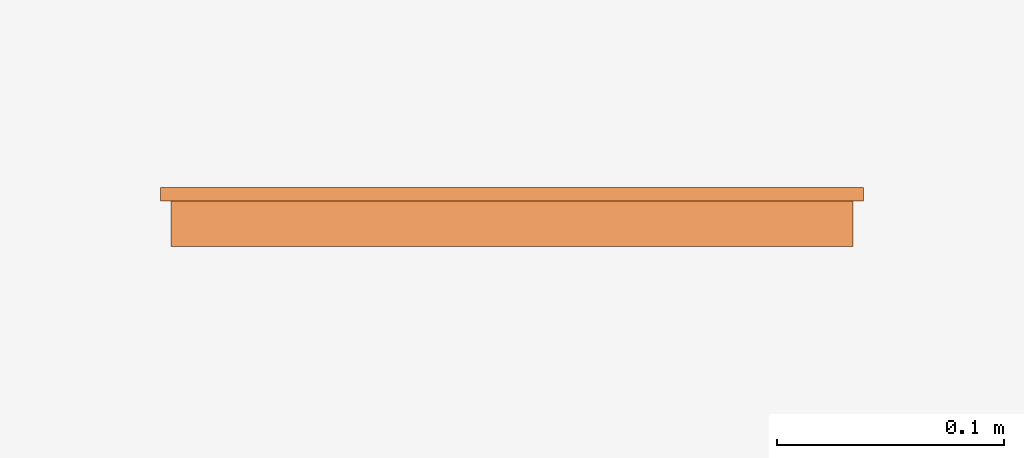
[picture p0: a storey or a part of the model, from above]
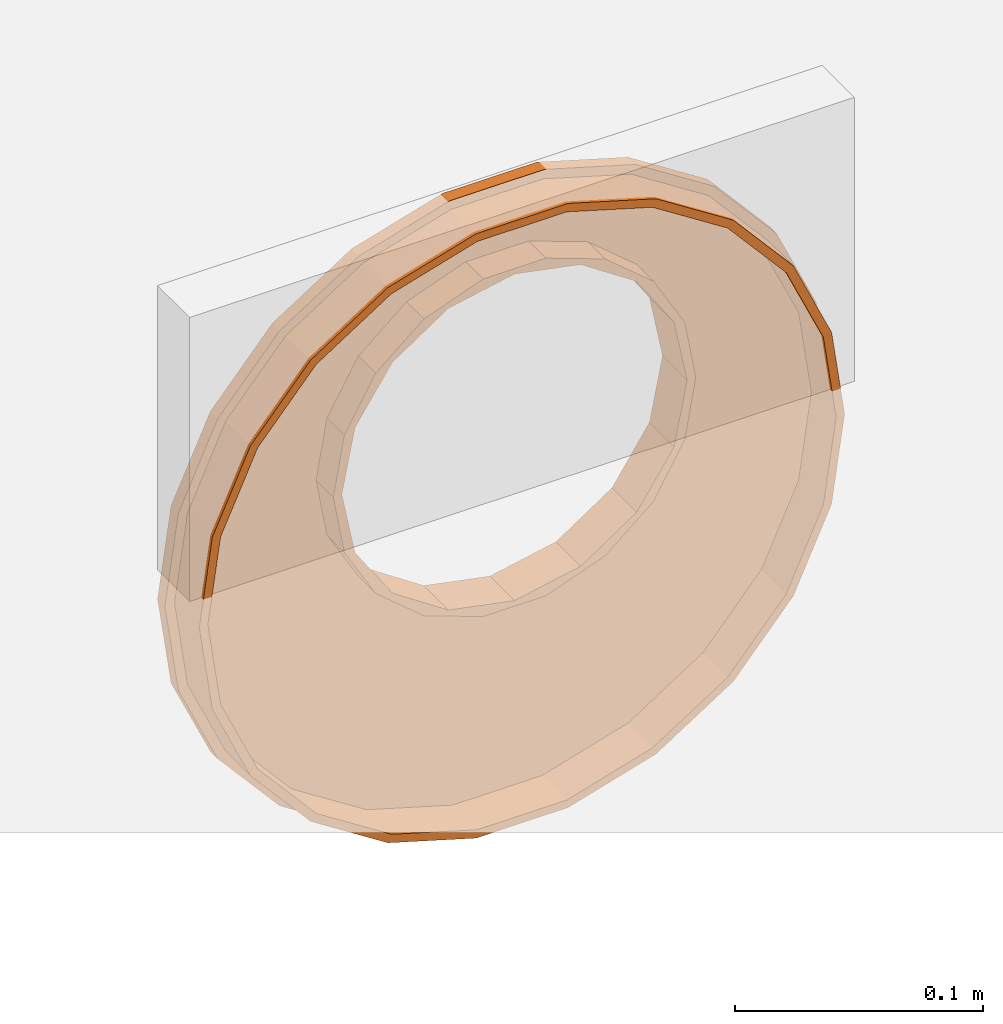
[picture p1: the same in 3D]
Properties of the parts of a building model (IFC2X3)

# File
Description: ViewDefinition [CoordinationView]
File name: 32995 - 150-225 Step Connector.ifc
Time: 2013-07-11T15:09:16
Written by: Autodesk Revit 2013
Made in: 20120221_2030(x64)

# IfcProject, Project Number
LongName: Project Name; Phase: Project Status

# IfcSite, Default
RefLatitude: 42, 21, 30, 344238; RefLongitude: -71, -3, -35, -194702; RefElevation: 0 mm

# IfcBuilding
Pset_BuildingCommon - NumberOfStoreys: 1
Other - Project Number: Project Number; Project Address: ## Street City, State Zip; Project Name: Project Name; Project Status: Project Status; Client Name: Owner; Project Issue Date: Issue Date

# IfcBuildingStorey, Level 1
LongName: Level 1; Elevation: 0 mm
Constraints - Elevation Base: 0; Elevation: 0 mm
Graphics - Line Pattern: Center; Symbol: M_Level Head - Circle: M_Level Head - Circle; Color: 0; Line Weight: 1; Symbol at End 2 Default: yes; Symbol at End 1 Default: no
Identity Data - Structural: no; Name: Level 1; Building Story: yes
Dimensions - Computation Height: 0 mm

# IfcBuildingElementProxy: 150-225 Step Connector, 150-225 Step Connector:150-225 Step Connector:150-225 Step Connector:536437
In: Level 1
Phasing - Phase Created: New Construction
Constraints - Moves With Nearby Elements: no; Level: Level: Level 1
Dimensions - Volume: 434498 mm3; Step Connector_Depth: 414.5 mm
Pset_BuildingElementProxyCommon - Reference: 150-225 Step Connector

# IfcOpeningElement: Opening
In: Level 1
Dimensions - Volume: 54034871603 mm3; Perimeter: 50000 mm; Thickness: 400 mm; Area: 135090000 mm2
Phasing - Phase Created: New Construction
Constraints - Height Offset From Level: 0 mm; Related to Mass: no; Room Bounding: yes; Level: Level: Level 1
Structural - Enable Analytical Model: no; Structural: no
Materials and Finishes - Structural Material: Plant
Analytical Properties - Roughness: 1; Absorptance: 0.1
Construction - Function: 0; Default Thickness: 400 mm
Graphics - Coarse Scale Fill Color: 0

# IfcSlab: Floor:Generic Floor - 400mm, Floor:Generic Floor - 400mm:193825
In: Level 1
PredefinedType: FLOOR; Material: Plant 400 mm
Dimensions - Volume: 54034871603 mm3; Perimeter: 50000 mm; Thickness: 400 mm; Area: 135090000 mm2
Phasing - Phase Created: New Construction
Constraints - Height Offset From Level: 0 mm; Related to Mass: no; Room Bounding: yes; Level: Level: Level 1
Structural - Enable Analytical Model: no; Structural: no
Pset_SlabCommon - Reference: Generic Floor - 400mm; IsExternal: no; LoadBearing: yes
Materials and Finishes - Structural Material: Plant
Analytical Properties - Roughness: 1; Absorptance: 0.1
Construction - Function: 0; Default Thickness: 400 mm
Graphics - Coarse Scale Fill Color: 0
